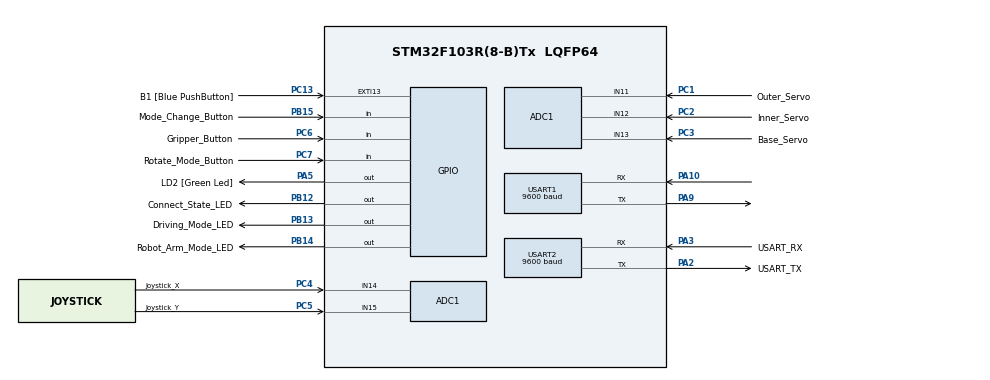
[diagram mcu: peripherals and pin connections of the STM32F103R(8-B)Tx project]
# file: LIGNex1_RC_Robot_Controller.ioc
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ADC1.Channel-0\#ChannelRegularConversion=ADC_CHANNEL_11
ADC1.Channel-1\#ChannelRegularConversion=ADC_CHANNEL_12
ADC1.Channel-2\#ChannelRegularConversion=ADC_CHANNEL_13
ADC1.Channel-3\#ChannelRegularConversion=ADC_CHANNEL_14
ADC1.Channel-4\#ChannelRegularConversion=ADC_CHANNEL_15
ADC1.ContinuousConvMode=ENABLE
ADC1.NbrOfConversion=5
ADC1.NbrOfConversionFlag=1
ADC1.Rank-0\#ChannelRegularConversion=1
ADC1.Rank-1\#ChannelRegularConversion=2
ADC1.Rank-2\#ChannelRegularConversion=3
ADC1.Rank-3\#ChannelRegularConversion=4
ADC1.Rank-4\#ChannelRegularConversion=5
ADC1.SamplingTime-0\#ChannelRegularConversion=ADC_SAMPLETIME_28CYCLES_5
ADC1.SamplingTime-1\#ChannelRegularConversion=ADC_SAMPLETIME_28CYCLES_5
ADC1.SamplingTime-2\#ChannelRegularConversion=ADC_SAMPLETIME_28CYCLES_5
ADC1.SamplingTime-3\#ChannelRegularConversion=ADC_SAMPLETIME_28CYCLES_5
ADC1.SamplingTime-4\#ChannelRegularConversion=ADC_SAMPLETIME_28CYCLES_5
ADC1.master=1
Dma.ADC1.2.Direction=DMA_PERIPH_TO_MEMORY
Dma.ADC1.2.Instance=DMA1_Channel1
Dma.ADC1.2.MemDataAlignment=DMA_MDATAALIGN_HALFWORD
Dma.ADC1.2.MemInc=DMA_MINC_ENABLE
Dma.ADC1.2.Mode=DMA_CIRCULAR
Dma.ADC1.2.PeriphDataAlignment=DMA_PDATAALIGN_HALFWORD
Dma.ADC1.2.PeriphInc=DMA_PINC_DISABLE
Dma.ADC1.2.Priority=DMA_PRIORITY_LOW
Dma.Request0=USART1_RX
Dma.Request1=USART1_TX
Dma.Request2=ADC1
Dma.USART1_RX.0.Direction=DMA_PERIPH_TO_MEMORY
Dma.USART1_RX.0.Instance=DMA1_Channel5
Dma.USART1_RX.0.MemDataAlignment=DMA_MDATAALIGN_BYTE
Dma.USART1_RX.0.MemInc=DMA_MINC_ENABLE
Dma.USART1_RX.0.Mode=DMA_CIRCULAR
Dma.USART1_RX.0.PeriphDataAlignment=DMA_PDATAALIGN_BYTE
Dma.USART1_RX.0.PeriphInc=DMA_PINC_DISABLE
Dma.USART1_RX.0.Priority=DMA_PRIORITY_LOW
Dma.USART1_TX.1.Direction=DMA_MEMORY_TO_PERIPH
Dma.USART1_TX.1.Instance=DMA1_Channel4
Dma.USART1_TX.1.MemDataAlignment=DMA_MDATAALIGN_BYTE
Dma.USART1_TX.1.MemInc=DMA_MINC_ENABLE
Dma.USART1_TX.1.Mode=DMA_NORMAL
Dma.USART1_TX.1.PeriphDataAlignment=DMA_PDATAALIGN_BYTE
Dma.USART1_TX.1.PeriphInc=DMA_PINC_DISABLE
Dma.USART1_TX.1.Priority=DMA_PRIORITY_LOW
FREERTOS.Queues01=RxQhandle,16,Data,0,Static,RxQhandleBuffer,RxQhandleControlBlock
FREERTOS.Tasks01=InputTask,24,128,InputTaskHandler,As weak,NULL,Static,InputTaskBuffer,InputTaskControlBlock;BluetoothRxTask,8,128,BluetoothRxTaskHandler,As external,NULL,Static,BluetoothRxTaskBuffer,BluetoothRxTaskControlBlock
FREERTOS.configMAX_TASK_NAME_LEN=32
Mcu.Family=STM32F1
Mcu.Name=STM32F103R(8-B)Tx
Mcu.Package=LQFP64
NVIC.DMA1_Channel1_IRQn=true\:5\:0\:false\:false\:true\:true\:false\:true\:true
NVIC.DMA1_Channel4_IRQn=true\:5\:0\:false\:false\:true\:true\:false\:true\:true
NVIC.DMA1_Channel5_IRQn=true\:5\:0\:false\:false\:true\:true\:false\:true\:true
NVIC.EXTI15_10_IRQn=true\:5\:0\:false\:false\:true\:true\:true\:true\:true
NVIC.PriorityGroup=NVIC_PRIORITYGROUP_4
NVIC.TIM4_IRQn=true\:15\:0\:false\:false\:true\:false\:false\:true\:true
NVIC.TimeBase=TIM4_IRQn
NVIC.TimeBaseIP=TIM4
NVIC.USART1_IRQn=true\:5\:0\:false\:false\:true\:true\:true\:true\:true
NVIC.USART2_IRQn=true\:5\:0\:false\:false\:true\:true\:true\:true\:true
PA10.Mode=Asynchronous
PA10.Signal=USART1_RX
PA13.GPIO_Label=TMS
PA13.Mode=Serial_Wire
PA13.Signal=SYS_JTMS-SWDIO
PA14.GPIO_Label=TCK
PA14.Mode=Serial_Wire
PA14.Signal=SYS_JTCK-SWCLK
PA2.GPIO_Label=USART_TX
PA2.GPIO_Mode=GPIO_MODE_AF_PP
PA2.GPIO_PuPd=GPIO_NOPULL
PA2.GPIO_Speed=GPIO_SPEED_FREQ_LOW
PA2.Mode=Asynchronous
PA2.Signal=USART2_TX
PA3.GPIO_Label=USART_RX
PA3.GPIO_Mode=GPIO_MODE_AF_PP
PA3.GPIO_PuPd=GPIO_NOPULL
PA3.GPIO_Speed=GPIO_SPEED_FREQ_LOW
PA3.Mode=Asynchronous
PA3.Signal=USART2_RX
PA5.GPIO_Label=LD2 [Green Led]
PA5.GPIO_ModeDefaultOutputPP=GPIO_MODE_OUTPUT_PP
PA5.GPIO_PuPd=GPIO_NOPULL
PA5.GPIO_Speed=GPIO_SPEED_FREQ_LOW
PA5.Signal=GPIO_Output
PA9.Mode=Asynchronous
PA9.Signal=USART1_TX
PB12.GPIO_Label=Connect_State_LED
PB12.Signal=GPIO_Output
PB13.GPIO_Label=Driving_Mode_LED
PB13.Signal=GPIO_Output
PB14.GPIO_Label=Robot_Arm_Mode_LED
PB14.Signal=GPIO_Output
PB15.GPIO_Label=Mode_Change_Button
PB15.GPIO_PuPd=GPIO_PULLDOWN
PB15.Signal=GPIO_Input
PB3.GPIO_Label=SWO
PB3.Signal=SYS_JTDO-TRACESWO
PC1.GPIO_Label=Outer_Servo
PC1.Signal=ADCx_IN11
PC13-TAMPER-RTC.GPIO_Label=B1 [Blue PushButton]
PC13-TAMPER-RTC.GPIO_PuPd=GPIO_NOPULL
PC13-TAMPER-RTC.Signal=GPXTI13
PC14-OSC32_IN.Mode=LSE-External-Oscillator
PC14-OSC32_IN.Signal=RCC_OSC32_IN
PC15-OSC32_OUT.Mode=LSE-External-Oscillator
PC15-OSC32_OUT.Signal=RCC_OSC32_OUT
PC2.GPIO_Label=Inner_Servo
PC2.Signal=ADCx_IN12
PC3.GPIO_Label=Base_Servo
PC3.Signal=ADCx_IN13
PC4.GPIO_Label=Joystick_X
PC4.Signal=ADCx_IN14
PC5.GPIO_Label=Joystick_Y
PC5.Signal=ADCx_IN15
PC6.GPIO_Label=Gripper_Button
PC6.GPIO_PuPd=GPIO_PULLDOWN
PC6.Signal=GPIO_Input
PC7.GPIO_Label=Rotate_Mode_Button
PC7.GPIO_PuPd=GPIO_PULLDOWN
PC7.Signal=GPIO_Input
PD0-OSC_IN.Mode=HSE-External-Clock-Source
PD0-OSC_IN.Signal=RCC_OSC_IN
PD1-OSC_OUT.Mode=HSE-External-Clock-Source
PD1-OSC_OUT.Signal=RCC_OSC_OUT
ProjectManager.HeapSize=0x200
ProjectManager.StackSize=0x400
ProjectManager.TargetToolchain=CMake
RCC.ADCPresc=RCC_ADCPCLK2_DIV6
RCC.AHBFreq_Value=72000000
RCC.APB1CLKDivider=RCC_HCLK_DIV2
RCC.APB1Freq_Value=36000000
RCC.APB1TimFreq_Value=72000000
RCC.APB2Freq_Value=72000000
RCC.APB2TimFreq_Value=72000000
RCC.HCLKFreq_Value=72000000
RCC.PLLMUL=RCC_PLL_MUL9
RCC.PLLSourceVirtual=RCC_PLLSOURCE_HSE
RCC.RTCClockSelection=RCC_RTCCLKSOURCE_LSE
RCC.SYSCLKFreq_VALUE=72000000
RCC.SYSCLKSource=RCC_SYSCLKSOURCE_PLLCLK
RCC.USBFreq_Value=72000000
SH.ADCx_IN11.0=ADC1_IN11,IN11
SH.ADCx_IN12.0=ADC1_IN12,IN12
SH.ADCx_IN13.0=ADC1_IN13,IN13
SH.ADCx_IN14.0=ADC1_IN14,IN14
SH.ADCx_IN15.0=ADC1_IN15,IN15
USART1.BaudRate=9600
USART1.VirtualMode=VM_ASYNC
USART2.BaudRate=9600
USART2.VirtualMode=VM_ASYNC
VP_FREERTOS_VS_CMSIS_V2.Mode=CMSIS_V2
VP_SYS_VS_tim4.Mode=TIM4
board=NUCLEO-F103RB

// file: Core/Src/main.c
/* USER CODE BEGIN Header */
/**
  ******************************************************************************
  * @file           : main.c
  * @brief          : Main program body
  ******************************************************************************
  * @attention
  *
  * Copyright (c) 2026 STMicroelectronics.
  * All rights reserved.
  *
  * This software is licensed under terms that can be found in the LICENSE file
  * in the root directory of this software component.
  * If no LICENSE file comes with this software, it is provided AS-IS.
  *
  ******************************************************************************
  */
/* USER CODE END Header */
#include "main.h"
#include "cmsis_os.h"
#include "adc.h"
#include "dma.h"
#include "usart.h"
#include "gpio.h"

/* USER CODE BEGIN PV */
extern ADC_HandleTypeDef hadc1;

/* USER CODE END PV */

void SystemClock_Config(void);
void MX_FREERTOS_Init(void);
/* USER CODE BEGIN PFP */
void SystemManager_Init(ADC_HandleTypeDef* hadc);
void SystemManager_Run(void);

/* USER CODE END PFP */

/* USER CODE BEGIN 0 */
int __io_putchar(int ch)
{
 if ( ch == '\n' )
	 HAL_UART_Transmit(&huart1, (uint8_t*)&"\r", 1, HAL_MAX_DELAY);
 HAL_UART_Transmit(&huart1, (uint8_t*)&ch, 1, HAL_MAX_DELAY);
 return ch;
}

int __io_getchar(void)
{
	uint8_t ch;

	while( HAL_OK != HAL_UART_Receive(&huart1, &ch, 1, HAL_MAX_DELAY) )
	{
		;
	}
	return ch;
}
/* USER CODE END 0 */

int main(void)
{

  /* MCU Configuration--------------------------------------------------------*/

  /* Reset of all peripherals, Initializes the Flash interface and the Systick. */
  HAL_Init();

  /* Configure the system clock */
  SystemClock_Config();

  /* Initialize all configured peripherals */
  MX_GPIO_Init();
  MX_DMA_Init();
  MX_USART2_UART_Init();
  MX_USART1_UART_Init();
  MX_ADC1_Init();
  /* USER CODE BEGIN 2 */
  SystemManager_Init(&hadc1);
  /* USER CODE END 2 */

  /* Init scheduler */
  osKernelInitialize();  /* Call init function for freertos objects (in cmsis_os2.c) */
  MX_FREERTOS_Init();

  /* Start scheduler */
  osKernelStart();

  /* We should never get here as control is now taken by the scheduler */

  /* Infinite loop */
  while (1)
  {

  }
}

void SystemClock_Config(void)
{
  RCC_OscInitTypeDef RCC_OscInitStruct = {0};
  RCC_ClkInitTypeDef RCC_ClkInitStruct = {0};
  RCC_PeriphCLKInitTypeDef PeriphClkInit = {0};

  /** Initializes the RCC Oscillators according to the specified parameters
  * in the RCC_OscInitTypeDef structure.
  */
  RCC_OscInitStruct.OscillatorType = RCC_OSCILLATORTYPE_HSI;
  RCC_OscInitStruct.HSIState = RCC_HSI_ON;
  RCC_OscInitStruct.HSICalibrationValue = RCC_HSICALIBRATION_DEFAULT;
  RCC_OscInitStruct.PLL.PLLState = RCC_PLL_ON;
  RCC_OscInitStruct.PLL.PLLSource = RCC_PLLSOURCE_HSI_DIV2;
  RCC_OscInitStruct.PLL.PLLMUL = RCC_PLL_MUL16;
  if (HAL_RCC_OscConfig(&RCC_OscInitStruct) != HAL_OK)
  {
    Error_Handler();
  }

  /** Initializes the CPU, AHB and APB buses clocks
  */
  RCC_ClkInitStruct.ClockType = RCC_CLOCKTYPE_HCLK|RCC_CLOCKTYPE_SYSCLK
                              |RCC_CLOCKTYPE_PCLK1|RCC_CLOCKTYPE_PCLK2;
  RCC_ClkInitStruct.SYSCLKSource = RCC_SYSCLKSOURCE_PLLCLK;
  RCC_ClkInitStruct.AHBCLKDivider = RCC_SYSCLK_DIV1;
  RCC_ClkInitStruct.APB1CLKDivider = RCC_HCLK_DIV2;
  RCC_ClkInitStruct.APB2CLKDivider = RCC_HCLK_DIV1;

  if (HAL_RCC_ClockConfig(&RCC_ClkInitStruct, FLASH_LATENCY_2) != HAL_OK)
  {
    Error_Handler();
  }
  PeriphClkInit.PeriphClockSelection = RCC_PERIPHCLK_ADC;
  PeriphClkInit.AdcClockSelection = RCC_ADCPCLK2_DIV8;
  if (HAL_RCCEx_PeriphCLKConfig(&PeriphClkInit) != HAL_OK)
  {
    Error_Handler();
  }
}

void HAL_TIM_PeriodElapsedCallback(TIM_HandleTypeDef *htim)
{
  if (htim->Instance == TIM4)
  {
    HAL_IncTick();
  }
}

void Error_Handler(void)
{
  __disable_irq();
  while (1)
  {
  }
}
